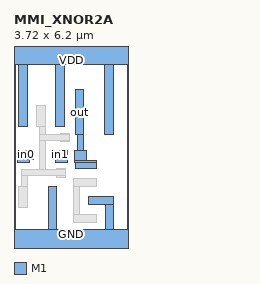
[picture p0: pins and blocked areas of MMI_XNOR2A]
MACRO MMI_XNOR2A
	CLASS CORE ;
	FOREIGN MMI_XNOR2A 0 0 ;
	SIZE 3.72 BY 6.2 ;
	SYMMETRY X Y ;
	SITE CORE1 ;
	PIN out
		DIRECTION output ;
		USE SIGNAL ;
		PORT
			LAYER M1 ;
			RECT 1.995 3.505 2.275 4.975 ;
			LAYER M1 ;
			RECT 2.07 2.98 2.265 3.505 ;
			LAYER M1 ;
			RECT 1.98 2.675 2.36 2.98 ;
			LAYER M1 ;
			RECT 1.98 2.6 2.7 2.675 ;
			LAYER M1 ;
			RECT 2 2.395 2.7 2.6 ;
		END
		AntennaDiffArea 0.9856 ;
	END out
	PIN in1
		DIRECTION input ;
		USE SIGNAL ;
		PORT
			LAYER M1 ;
			RECT 1.27 2.7 1.74 2.98 ;
			LAYER M1 ;
			RECT 1.36 2.6 1.74 2.7 ;
		END
		AntennaGateArea 0.5775 ;
	END in1
	PIN GND
		DIRECTION inout ;
		USE GROUND ;
		PORT
			LAYER M1 ;
			RECT 1.12 0.42 1.4 1.82 ;
			LAYER M1 ;
			RECT 2.42 1.215 3.255 1.495 ;
			LAYER M1 ;
			RECT 2.97 0.42 3.255 1.215 ;
			LAYER M1 ;
			RECT 0 -0.42 3.72 0.42 ;
		END
	END GND
	PIN VDD
		DIRECTION inout ;
		USE POWER ;
		PORT
			LAYER M1 ;
			RECT 0 5.78 3.72 6.62 ;
			LAYER M1 ;
			RECT 0.16 3.755 0.44 5.78 ;
			LAYER M1 ;
			RECT 1.355 3.755 1.635 5.78 ;
			LAYER M1 ;
			RECT 2.96 3.505 3.24 5.78 ;
		END
	END VDD
	PIN in0
		DIRECTION input ;
		USE SIGNAL ;
		PORT
			LAYER M1 ;
			RECT 0.12 2.7 0.635 2.98 ;
			LAYER M1 ;
			RECT 0.12 2.6 0.5 2.7 ;
		END
		AntennaGateArea 0.5775 ;
	END in0
	OBS
		LAYER M1 ;
		RECT 0.75 3.755 1.03 4.455 ;
		LAYER M1 ;
		RECT 0.84 3.505 1.03 3.755 ;
		LAYER M1 ;
		RECT 1.515 3.505 1.795 3.55 ;
		LAYER M1 ;
		RECT 0.84 3.315 1.795 3.505 ;
		LAYER M1 ;
		RECT 0.84 2.35 1.03 3.315 ;
		LAYER M1 ;
		RECT 1.515 3.27 1.795 3.315 ;
		LAYER M1 ;
		RECT 1.385 2.35 1.665 2.395 ;
		LAYER M1 ;
		RECT 0.245 2.16 1.665 2.35 ;
		LAYER M1 ;
		RECT 0.245 1.82 0.435 2.16 ;
		LAYER M1 ;
		RECT 1.385 2.115 1.665 2.16 ;
		LAYER M1 ;
		RECT 0.16 1.12 0.44 1.82 ;
		LAYER M1 ;
		RECT 1.95 1.805 2.7 2.085 ;
		LAYER M1 ;
		RECT 1.95 0.905 2.14 1.805 ;
		LAYER M1 ;
		RECT 1.95 0.625 2.7 0.905 ;
	END
END MMI_XNOR2A
